VERSION 5.7 ;
  NOWIREEXTENSIONATPIN ON ;
  DIVIDERCHAR "/" ;
  BUSBITCHARS "[]" ;
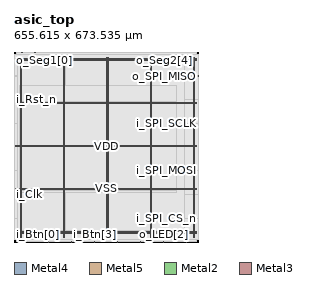
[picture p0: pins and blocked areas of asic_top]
MACRO asic_top
  CLASS BLOCK ;
  FOREIGN asic_top ;
  ORIGIN 0.000 0.000 ;
  SIZE 655.615 BY 673.535 ;
  PIN VDD
    DIRECTION INOUT ;
    USE POWER ;
    PORT
      LAYER Metal4 ;
        RECT 22.240 15.380 23.840 654.940 ;
    END
    PORT
      LAYER Metal4 ;
        RECT 175.840 15.380 177.440 654.940 ;
    END
    PORT
      LAYER Metal4 ;
        RECT 329.440 15.380 331.040 654.940 ;
    END
    PORT
      LAYER Metal4 ;
        RECT 483.040 15.380 484.640 654.940 ;
    END
    PORT
      LAYER Metal4 ;
        RECT 636.640 15.380 638.240 654.940 ;
    END
    PORT
      LAYER Metal5 ;
        RECT 6.720 31.530 648.480 33.130 ;
    END
    PORT
      LAYER Metal5 ;
        RECT 6.720 184.710 648.480 186.310 ;
    END
    PORT
      LAYER Metal5 ;
        RECT 6.720 337.890 648.480 339.490 ;
    END
    PORT
      LAYER Metal5 ;
        RECT 6.720 491.070 648.480 492.670 ;
    END
    PORT
      LAYER Metal5 ;
        RECT 6.720 644.250 648.480 645.850 ;
    END
  END VDD
  PIN VSS
    DIRECTION INOUT ;
    USE GROUND ;
    PORT
      LAYER Metal4 ;
        RECT 25.540 15.380 27.140 654.940 ;
    END
    PORT
      LAYER Metal4 ;
        RECT 179.140 15.380 180.740 654.940 ;
    END
    PORT
      LAYER Metal4 ;
        RECT 332.740 15.380 334.340 654.940 ;
    END
    PORT
      LAYER Metal4 ;
        RECT 486.340 15.380 487.940 654.940 ;
    END
    PORT
      LAYER Metal4 ;
        RECT 639.940 15.380 641.540 654.940 ;
    END
    PORT
      LAYER Metal5 ;
        RECT 6.720 34.830 648.480 36.430 ;
    END
    PORT
      LAYER Metal5 ;
        RECT 6.720 188.010 648.480 189.610 ;
    END
    PORT
      LAYER Metal5 ;
        RECT 6.720 341.190 648.480 342.790 ;
    END
    PORT
      LAYER Metal5 ;
        RECT 6.720 494.370 648.480 495.970 ;
    END
    PORT
      LAYER Metal5 ;
        RECT 6.720 647.550 648.480 649.150 ;
    END
  END VSS
  PIN i_Btn[0]
    DIRECTION INPUT ;
    USE SIGNAL ;
    ANTENNAGATEAREA 0.396000 ;
    PORT
      LAYER Metal2 ;
        RECT 40.320 0.000 40.880 0.560 ;
    END
  END i_Btn[0]
  PIN i_Btn[1]
    DIRECTION INPUT ;
    USE SIGNAL ;
    ANTENNAGATEAREA 0.396000 ;
    PORT
      LAYER Metal2 ;
        RECT 122.080 0.000 122.640 0.560 ;
    END
  END i_Btn[1]
  PIN i_Btn[2]
    DIRECTION INPUT ;
    USE SIGNAL ;
    ANTENNAGATEAREA 0.396000 ;
    PORT
      LAYER Metal2 ;
        RECT 203.840 0.000 204.400 0.560 ;
    END
  END i_Btn[2]
  PIN i_Btn[3]
    DIRECTION INPUT ;
    USE SIGNAL ;
    ANTENNAGATEAREA 0.396000 ;
    PORT
      LAYER Metal2 ;
        RECT 285.600 0.000 286.160 0.560 ;
    END
  END i_Btn[3]
  PIN i_Clk
    DIRECTION INPUT ;
    USE SIGNAL ;
    ANTENNAGATEAREA 4.738000 ;
    PORT
      LAYER Metal3 ;
        RECT 0.000 168.000 0.560 168.560 ;
    END
  END i_Clk
  PIN i_Rst_n
    DIRECTION INPUT ;
    USE SIGNAL ;
    ANTENNAGATEAREA 0.396000 ;
    PORT
      LAYER Metal3 ;
        RECT 0.000 504.000 0.560 504.560 ;
    END
  END i_Rst_n
  PIN i_SPI_CS_n
    DIRECTION INPUT ;
    USE SIGNAL ;
    ANTENNAGATEAREA 0.396000 ;
    PORT
      LAYER Metal3 ;
        RECT 655.055 84.000 655.615 84.560 ;
    END
  END i_SPI_CS_n
  PIN i_SPI_MOSI
    DIRECTION INPUT ;
    USE SIGNAL ;
    ANTENNAGATEAREA 0.396000 ;
    PORT
      LAYER Metal3 ;
        RECT 655.055 252.000 655.615 252.560 ;
    END
  END i_SPI_MOSI
  PIN i_SPI_SCLK
    DIRECTION INPUT ;
    USE SIGNAL ;
    ANTENNAGATEAREA 0.396000 ;
    PORT
      LAYER Metal3 ;
        RECT 655.055 420.000 655.615 420.560 ;
    END
  END i_SPI_SCLK
  PIN o_LED[0]
    DIRECTION OUTPUT ;
    USE SIGNAL ;
    ANTENNADIFFAREA 0.897600 ;
    PORT
      LAYER Metal2 ;
        RECT 367.360 0.000 367.920 0.560 ;
    END
  END o_LED[0]
  PIN o_LED[1]
    DIRECTION OUTPUT ;
    USE SIGNAL ;
    ANTENNADIFFAREA 0.897600 ;
    PORT
      LAYER Metal2 ;
        RECT 449.120 0.000 449.680 0.560 ;
    END
  END o_LED[1]
  PIN o_LED[2]
    DIRECTION OUTPUT ;
    USE SIGNAL ;
    ANTENNADIFFAREA 0.897600 ;
    PORT
      LAYER Metal2 ;
        RECT 530.880 0.000 531.440 0.560 ;
    END
  END o_LED[2]
  PIN o_LED[3]
    DIRECTION OUTPUT ;
    USE SIGNAL ;
    ANTENNADIFFAREA 0.897600 ;
    PORT
      LAYER Metal2 ;
        RECT 612.640 0.000 613.200 0.560 ;
    END
  END o_LED[3]
  PIN o_SPI_MISO
    DIRECTION OUTPUT ;
    USE SIGNAL ;
    ANTENNADIFFAREA 0.897600 ;
    PORT
      LAYER Metal3 ;
        RECT 655.055 588.000 655.615 588.560 ;
    END
  END o_SPI_MISO
  PIN o_Seg1[0]
    DIRECTION OUTPUT ;
    USE SIGNAL ;
    ANTENNADIFFAREA 0.897600 ;
    PORT
      LAYER Metal2 ;
        RECT 28.000 672.975 28.560 673.535 ;
    END
  END o_Seg1[0]
  PIN o_Seg1[1]
    DIRECTION OUTPUT ;
    USE SIGNAL ;
    ANTENNADIFFAREA 0.897600 ;
    PORT
      LAYER Metal2 ;
        RECT 73.920 672.975 74.480 673.535 ;
    END
  END o_Seg1[1]
  PIN o_Seg1[2]
    DIRECTION OUTPUT ;
    USE SIGNAL ;
    ANTENNADIFFAREA 0.897600 ;
    PORT
      LAYER Metal2 ;
        RECT 119.840 672.975 120.400 673.535 ;
    END
  END o_Seg1[2]
  PIN o_Seg1[3]
    DIRECTION OUTPUT ;
    USE SIGNAL ;
    ANTENNADIFFAREA 0.897600 ;
    PORT
      LAYER Metal2 ;
        RECT 165.760 672.975 166.320 673.535 ;
    END
  END o_Seg1[3]
  PIN o_Seg1[4]
    DIRECTION OUTPUT ;
    USE SIGNAL ;
    ANTENNADIFFAREA 0.897600 ;
    PORT
      LAYER Metal2 ;
        RECT 211.680 672.975 212.240 673.535 ;
    END
  END o_Seg1[4]
  PIN o_Seg1[5]
    DIRECTION OUTPUT ;
    USE SIGNAL ;
    ANTENNADIFFAREA 0.897600 ;
    PORT
      LAYER Metal2 ;
        RECT 257.600 672.975 258.160 673.535 ;
    END
  END o_Seg1[5]
  PIN o_Seg1[6]
    DIRECTION OUTPUT ;
    USE SIGNAL ;
    ANTENNADIFFAREA 0.897600 ;
    PORT
      LAYER Metal2 ;
        RECT 303.520 672.975 304.080 673.535 ;
    END
  END o_Seg1[6]
  PIN o_Seg2[0]
    DIRECTION OUTPUT ;
    USE SIGNAL ;
    ANTENNADIFFAREA 0.897600 ;
    PORT
      LAYER Metal2 ;
        RECT 349.440 672.975 350.000 673.535 ;
    END
  END o_Seg2[0]
  PIN o_Seg2[1]
    DIRECTION OUTPUT ;
    USE SIGNAL ;
    ANTENNADIFFAREA 0.897600 ;
    PORT
      LAYER Metal2 ;
        RECT 395.360 672.975 395.920 673.535 ;
    END
  END o_Seg2[1]
  PIN o_Seg2[2]
    DIRECTION OUTPUT ;
    USE SIGNAL ;
    ANTENNADIFFAREA 0.897600 ;
    PORT
      LAYER Metal2 ;
        RECT 441.280 672.975 441.840 673.535 ;
    END
  END o_Seg2[2]
  PIN o_Seg2[3]
    DIRECTION OUTPUT ;
    USE SIGNAL ;
    ANTENNADIFFAREA 0.897600 ;
    PORT
      LAYER Metal2 ;
        RECT 487.200 672.975 487.760 673.535 ;
    END
  END o_Seg2[3]
  PIN o_Seg2[4]
    DIRECTION OUTPUT ;
    USE SIGNAL ;
    ANTENNADIFFAREA 0.897600 ;
    PORT
      LAYER Metal2 ;
        RECT 533.120 672.975 533.680 673.535 ;
    END
  END o_Seg2[4]
  PIN o_Seg2[5]
    DIRECTION OUTPUT ;
    USE SIGNAL ;
    ANTENNADIFFAREA 0.897600 ;
    PORT
      LAYER Metal2 ;
        RECT 579.040 672.975 579.600 673.535 ;
    END
  END o_Seg2[5]
  PIN o_Seg2[6]
    DIRECTION OUTPUT ;
    USE SIGNAL ;
    ANTENNADIFFAREA 0.897600 ;
    PORT
      LAYER Metal2 ;
        RECT 624.960 672.975 625.520 673.535 ;
    END
  END o_Seg2[6]
  OBS
      LAYER Nwell ;
        RECT 6.290 15.250 648.910 655.070 ;
      LAYER Metal1 ;
        RECT 6.720 15.380 648.480 654.940 ;
      LAYER Metal2 ;
        RECT 8.540 672.675 27.700 672.975 ;
        RECT 28.860 672.675 73.620 672.975 ;
        RECT 74.780 672.675 119.540 672.975 ;
        RECT 120.700 672.675 165.460 672.975 ;
        RECT 166.620 672.675 211.380 672.975 ;
        RECT 212.540 672.675 257.300 672.975 ;
        RECT 258.460 672.675 303.220 672.975 ;
        RECT 304.380 672.675 349.140 672.975 ;
        RECT 350.300 672.675 395.060 672.975 ;
        RECT 396.220 672.675 440.980 672.975 ;
        RECT 442.140 672.675 486.900 672.975 ;
        RECT 488.060 672.675 532.820 672.975 ;
        RECT 533.980 672.675 578.740 672.975 ;
        RECT 579.900 672.675 624.660 672.975 ;
        RECT 625.820 672.675 647.220 672.975 ;
        RECT 8.540 0.860 647.220 672.675 ;
        RECT 8.540 0.560 40.020 0.860 ;
        RECT 41.180 0.560 121.780 0.860 ;
        RECT 122.940 0.560 203.540 0.860 ;
        RECT 204.700 0.560 285.300 0.860 ;
        RECT 286.460 0.560 367.060 0.860 ;
        RECT 368.220 0.560 448.820 0.860 ;
        RECT 449.980 0.560 530.580 0.860 ;
        RECT 531.740 0.560 612.340 0.860 ;
        RECT 613.500 0.560 647.220 0.860 ;
      LAYER Metal3 ;
        RECT 0.560 588.860 655.055 663.460 ;
        RECT 0.560 587.700 654.755 588.860 ;
        RECT 0.560 504.860 655.055 587.700 ;
        RECT 0.860 503.700 655.055 504.860 ;
        RECT 0.560 420.860 655.055 503.700 ;
        RECT 0.560 419.700 654.755 420.860 ;
        RECT 0.560 252.860 655.055 419.700 ;
        RECT 0.560 251.700 654.755 252.860 ;
        RECT 0.560 168.860 655.055 251.700 ;
        RECT 0.860 167.700 655.055 168.860 ;
        RECT 0.560 84.860 655.055 167.700 ;
        RECT 0.560 83.700 654.755 84.860 ;
        RECT 0.560 9.100 655.055 83.700 ;
      LAYER Metal4 ;
        RECT 14.140 39.850 21.940 646.710 ;
        RECT 24.140 39.850 25.240 646.710 ;
        RECT 27.440 39.850 175.540 646.710 ;
        RECT 177.740 39.850 178.840 646.710 ;
        RECT 181.040 39.850 329.140 646.710 ;
        RECT 331.340 39.850 332.440 646.710 ;
        RECT 334.640 39.850 482.740 646.710 ;
        RECT 484.940 39.850 486.040 646.710 ;
        RECT 488.240 39.850 604.660 646.710 ;
      LAYER Metal5 ;
        RECT 19.100 496.570 575.060 555.970 ;
        RECT 19.100 493.270 575.060 493.770 ;
        RECT 19.100 343.390 575.060 490.470 ;
        RECT 19.100 340.090 575.060 340.590 ;
        RECT 19.100 190.210 575.060 337.290 ;
        RECT 19.100 186.910 575.060 187.410 ;
        RECT 19.100 174.830 575.060 184.110 ;
  END
END asic_top
END LIBRARY

